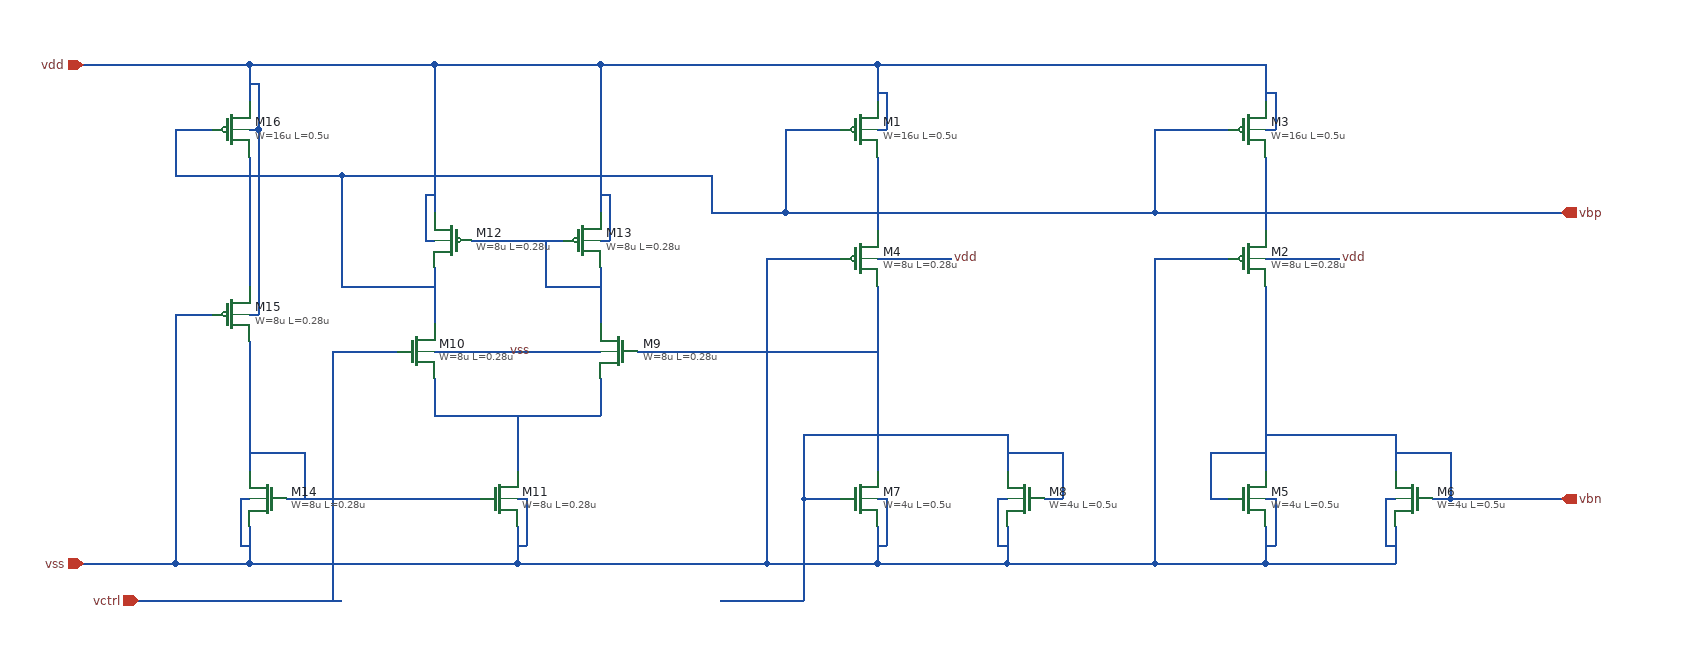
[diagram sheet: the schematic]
v {xschem version=3.4.5 file_version=1.2
}
G {}
K {}
V {}
S {}
E {}
N 1120 -460 1120 -420 {
lab=#net1}
N 1120 -500 1120 -460 {
lab=#net1}
N 1120 -600 1120 -560 {
lab=vdd}
N 1120 -530 1130 -530 {
lab=vdd}
N 1130 -570 1130 -530 {
lab=vdd}
N 1120 -570 1130 -570 {
lab=vdd}
N 1120 -390 1200 -390 {
lab=vdd}
N 1000 -390 1080 -390 {
lab=vss}
N 1120 -360 1120 -280 {
lab=vbn}
N 1120 -280 1120 -160 {
lab=vbn}
N 1120 -100 1120 -60 {
lab=vss}
N 1120 -130 1130 -130 {
lab=vss}
N 1130 -130 1130 -80 {
lab=vss}
N 1120 -80 1130 -80 {
lab=vss}
N 1260 -100 1260 -60 {
lab=vss}
N 1120 -60 1260 -60 {
lab=vss}
N 1250 -130 1260 -130 {
lab=vss}
N 1250 -130 1250 -80 {
lab=vss}
N 1250 -80 1260 -80 {
lab=vss}
N 1260 -200 1260 -160 {
lab=vbn}
N 1120 -200 1260 -200 {
lab=vbn}
N 1300 -130 1320 -130 {
lab=vbn}
N 1060 -130 1080 -130 {
lab=vbn}
N 1060 -180 1060 -130 {
lab=vbn}
N 1060 -180 1120 -180 {
lab=vbn}
N 1320 -130 1440 -130 {
lab=vbn}
N 1000 -390 1000 -60 {
lab=vss}
N 1000 -60 1120 -60 {
lab=vss}
N 1000 -530 1080 -530 {
lab=vbp}
N 1000 -530 1000 -440 {
lab=vbp}
N 920 -440 1000 -440 {
lab=vbp}
N 1000 -440 1440 -440 {
lab=vbp}
N 700 -460 700 -420 {
lab=#net2}
N 700 -500 700 -460 {
lab=#net2}
N 700 -600 700 -560 {
lab=vdd}
N 700 -530 710 -530 {
lab=vdd}
N 710 -570 710 -530 {
lab=vdd}
N 700 -570 710 -570 {
lab=vdd}
N 700 -390 780 -390 {
lab=vdd}
N 700 -360 700 -280 {
lab=vctrl}
N 700 -280 700 -160 {
lab=vctrl}
N 700 -100 700 -60 {
lab=vss}
N 700 -130 710 -130 {
lab=vss}
N 710 -130 710 -80 {
lab=vss}
N 700 -80 710 -80 {
lab=vss}
N 840 -100 840 -60 {
lab=vss}
N 700 -60 840 -60 {
lab=vss}
N 830 -130 840 -130 {
lab=vss}
N 830 -130 830 -80 {
lab=vss}
N 830 -80 840 -80 {
lab=vss}
N 840 -200 840 -160 {
lab=vctrl}
N 700 -200 840 -200 {
lab=vctrl}
N 880 -130 900 -130 {
lab=vctrl}
N 900 -180 900 -130 {
lab=vctrl}
N 840 -180 900 -180 {
lab=vctrl}
N 840 -60 1000 -60 {
lab=vss}
N 600 -530 660 -530 {
lab=vbp}
N 600 -530 600 -440 {
lab=vbp}
N 600 -440 920 -440 {
lab=vbp}
N 580 -390 660 -390 {
lab=vss}
N 580 -390 580 -60 {
lab=vss}
N 580 -60 700 -60 {
lab=vss}
N 620 -130 660 -130 {
lab=vctrl}
N 620 -130 620 -20 {
lab=vctrl}
N 530 -20 620 -20 {
lab=vctrl}
N 700 -600 1120 -600 {
lab=vdd}
N 220 -260 220 -220 {
lab=#net3}
N 220 -220 400 -220 {
lab=#net3}
N 400 -260 400 -220 {
lab=#net3}
N 120 -290 180 -290 {
lab=vctrl}
N 440 -290 500 -290 {
lab=vctrl}
N 310 -220 310 -160 {
lab=#net3}
N 310 -100 310 -60 {
lab=vss}
N 310 -60 580 -60 {
lab=vss}
N 310 -130 320 -130 {
lab=vss}
N 320 -130 320 -80 {
lab=vss}
N 310 -80 320 -80 {
lab=vss}
N 200 -130 270 -130 {
lab=#net4}
N 220 -290 400 -290 {
lab=vss}
N 220 -380 220 -320 {
lab=vbp}
N 400 -380 400 -320 {
lab=#net5}
N 220 -600 220 -440 {
lab=vdd}
N 220 -600 400 -600 {
lab=vdd}
N 400 -600 400 -440 {
lab=vdd}
N 260 -410 360 -410 {
lab=#net5}
N 340 -360 400 -360 {
lab=#net5}
N 340 -410 340 -360 {
lab=#net5}
N 400 -410 410 -410 {
lab=vdd}
N 410 -460 410 -410 {
lab=vdd}
N 400 -460 410 -460 {
lab=vdd}
N 210 -410 220 -410 {
lab=vdd}
N 210 -460 210 -410 {
lab=vdd}
N 210 -460 220 -460 {
lab=vdd}
N 20 -100 20 -60 {
lab=vss}
N 20 -60 310 -60 {
lab=vss}
N 20 -300 20 -160 {
lab=#net4}
N 60 -130 200 -130 {
lab=#net4}
N 20 -180 80 -180 {
lab=#net4}
N 80 -180 80 -130 {
lab=#net4}
N 10 -130 20 -130 {
lab=vss}
N 10 -130 10 -80 {
lab=vss}
N 10 -80 20 -80 {
lab=vss}
N -60 -330 -20 -330 {
lab=vss}
N -60 -330 -60 -60 {
lab=vss}
N -60 -60 20 -60 {
lab=vss}
N 20 -440 20 -360 {
lab=#net6}
N 20 -500 20 -440 {
lab=#net6}
N 20 -600 20 -560 {
lab=vdd}
N 20 -600 220 -600 {
lab=vdd}
N 20 -530 30 -530 {
lab=vdd}
N 30 -580 30 -530 {
lab=vdd}
N 20 -580 30 -580 {
lab=vdd}
N 20 -330 30 -330 {
lab=vdd}
N 30 -530 30 -330 {
lab=vdd}
N 120 -360 220 -360 {
lab=vbp}
N 120 -480 120 -360 {
lab=vbp}
N -60 -480 120 -480 {
lab=vbp}
N -60 -530 -60 -480 {
lab=vbp}
N -60 -530 -20 -530 {
lab=vbp}
N 120 -480 520 -480 {
lab=vbp}
N 520 -480 520 -440 {
lab=vbp}
N 520 -440 600 -440 {
lab=vbp}
N -100 -20 120 -20 {
lab=vctrl}
N 500 -290 700 -290 {
lab=vctrl}
N 400 -600 700 -600 {
lab=vdd}
N -80 -600 20 -600 {
lab=vdd}
N -100 -60 -60 -60 {
lab=vss}
N -160 -60 -100 -60 {
lab=vss}
N -160 -600 -80 -600 {
lab=vdd}
N 110 -290 110 -280 {
lab=vctrl}
N 110 -290 120 -290 {
lab=vctrl}
N 1260 -180 1320 -180 {
lab=vbn}
N 1320 -180 1320 -140 {
lab=vbn}
N 1320 -140 1320 -130 {
lab=vbn}
N 110 -280 110 -20 {
lab=vctrl}
N 620 -200 620 -130 {
lab=vctrl}
N 620 -200 700 -200 {
lab=vctrl}
C {symbols/pfet_03v3.sym} 1100 -530 0 0 {name=M3
L=0.5u
W=16u
nf=1
m=1
ad="'int((nf+1)/2) * W/nf * 0.18u'"
pd="'2*int((nf+1)/2) * (W/nf + 0.18u)'"
as="'int((nf+2)/2) * W/nf * 0.18u'"
ps="'2*int((nf+2)/2) * (W/nf + 0.18u)'"
nrd="'0.18u / W'" nrs="'0.18u / W'"
sa=0 sb=0 sd=0
model=pfet_03v3
spiceprefix=X
}
C {symbols/pfet_03v3.sym} 1100 -390 0 0 {name=M2
L=0.28u
W=8u
nf=1
m=2
ad="'int((nf+1)/2) * W/nf * 0.18u'"
pd="'2*int((nf+1)/2) * (W/nf + 0.18u)'"
as="'int((nf+2)/2) * W/nf * 0.18u'"
ps="'2*int((nf+2)/2) * (W/nf + 0.18u)'"
nrd="'0.18u / W'" nrs="'0.18u / W'"
sa=0 sb=0 sd=0
model=pfet_03v3
spiceprefix=X
}
C {symbols/nfet_03v3.sym} 1100 -130 0 0 {name=M5
L=0.5u
W=4u
nf=1
m=1
ad="'int((nf+1)/2) * W/nf * 0.18u'"
pd="'2*int((nf+1)/2) * (W/nf + 0.18u)'"
as="'int((nf+2)/2) * W/nf * 0.18u'"
ps="'2*int((nf+2)/2) * (W/nf + 0.18u)'"
nrd="'0.18u / W'" nrs="'0.18u / W'"
sa=0 sb=0 sd=0
model=nfet_03v3
spiceprefix=X
}
C {symbols/nfet_03v3.sym} 1280 -130 0 1 {name=M6
L=0.5u
W=4u
nf=1
m=1
ad="'int((nf+1)/2) * W/nf * 0.18u'"
pd="'2*int((nf+1)/2) * (W/nf + 0.18u)'"
as="'int((nf+2)/2) * W/nf * 0.18u'"
ps="'2*int((nf+2)/2) * (W/nf + 0.18u)'"
nrd="'0.18u / W'" nrs="'0.18u / W'"
sa=0 sb=0 sd=0
model=nfet_03v3
spiceprefix=X
}
C {lab_wire.sym} 1200 -390 0 1 {name=p10 sig_type=std_logic lab=vdd}
C {symbols/pfet_03v3.sym} 680 -530 0 0 {name=M1
L=0.5u
W=16u
nf=1
m=1
ad="'int((nf+1)/2) * W/nf * 0.18u'"
pd="'2*int((nf+1)/2) * (W/nf + 0.18u)'"
as="'int((nf+2)/2) * W/nf * 0.18u'"
ps="'2*int((nf+2)/2) * (W/nf + 0.18u)'"
nrd="'0.18u / W'" nrs="'0.18u / W'"
sa=0 sb=0 sd=0
model=pfet_03v3
spiceprefix=X
}
C {symbols/pfet_03v3.sym} 680 -390 0 0 {name=M4
L=0.28u
W=8u
nf=1
m=2
ad="'int((nf+1)/2) * W/nf * 0.18u'"
pd="'2*int((nf+1)/2) * (W/nf + 0.18u)'"
as="'int((nf+2)/2) * W/nf * 0.18u'"
ps="'2*int((nf+2)/2) * (W/nf + 0.18u)'"
nrd="'0.18u / W'" nrs="'0.18u / W'"
sa=0 sb=0 sd=0
model=pfet_03v3
spiceprefix=X
}
C {symbols/nfet_03v3.sym} 680 -130 0 0 {name=M7
L=0.5u
W=4u
nf=1
m=1
ad="'int((nf+1)/2) * W/nf * 0.18u'"
pd="'2*int((nf+1)/2) * (W/nf + 0.18u)'"
as="'int((nf+2)/2) * W/nf * 0.18u'"
ps="'2*int((nf+2)/2) * (W/nf + 0.18u)'"
nrd="'0.18u / W'" nrs="'0.18u / W'"
sa=0 sb=0 sd=0
model=nfet_03v3
spiceprefix=X
}
C {symbols/nfet_03v3.sym} 860 -130 0 1 {name=M8
L=0.5u
W=4u
nf=1
m=1
ad="'int((nf+1)/2) * W/nf * 0.18u'"
pd="'2*int((nf+1)/2) * (W/nf + 0.18u)'"
as="'int((nf+2)/2) * W/nf * 0.18u'"
ps="'2*int((nf+2)/2) * (W/nf + 0.18u)'"
nrd="'0.18u / W'" nrs="'0.18u / W'"
sa=0 sb=0 sd=0
model=nfet_03v3
spiceprefix=X
}
C {lab_wire.sym} 780 -390 0 1 {name=p1 sig_type=std_logic lab=vdd}
C {symbols/nfet_03v3.sym} 420 -290 0 1 {name=M9
L=0.28u
W=8u
nf=1
m=2
ad="'int((nf+1)/2) * W/nf * 0.18u'"
pd="'2*int((nf+1)/2) * (W/nf + 0.18u)'"
as="'int((nf+2)/2) * W/nf * 0.18u'"
ps="'2*int((nf+2)/2) * (W/nf + 0.18u)'"
nrd="'0.18u / W'" nrs="'0.18u / W'"
sa=0 sb=0 sd=0
model=nfet_03v3
spiceprefix=X
}
C {symbols/nfet_03v3.sym} 200 -290 0 0 {name=M10
L=0.28u
W=8u
nf=1
m=2
ad="'int((nf+1)/2) * W/nf * 0.18u'"
pd="'2*int((nf+1)/2) * (W/nf + 0.18u)'"
as="'int((nf+2)/2) * W/nf * 0.18u'"
ps="'2*int((nf+2)/2) * (W/nf + 0.18u)'"
nrd="'0.18u / W'" nrs="'0.18u / W'"
sa=0 sb=0 sd=0
model=nfet_03v3
spiceprefix=X
}
C {symbols/nfet_03v3.sym} 290 -130 0 0 {name=M11
L=0.28u
W=8u
nf=1
m=1
ad="'int((nf+1)/2) * W/nf * 0.18u'"
pd="'2*int((nf+1)/2) * (W/nf + 0.18u)'"
as="'int((nf+2)/2) * W/nf * 0.18u'"
ps="'2*int((nf+2)/2) * (W/nf + 0.18u)'"
nrd="'0.18u / W'" nrs="'0.18u / W'"
sa=0 sb=0 sd=0
model=nfet_03v3
spiceprefix=X
}
C {symbols/pfet_03v3.sym} 240 -410 0 1 {name=M12
L=0.28u
W=8u
nf=1
m=4
ad="'int((nf+1)/2) * W/nf * 0.18u'"
pd="'2*int((nf+1)/2) * (W/nf + 0.18u)'"
as="'int((nf+2)/2) * W/nf * 0.18u'"
ps="'2*int((nf+2)/2) * (W/nf + 0.18u)'"
nrd="'0.18u / W'" nrs="'0.18u / W'"
sa=0 sb=0 sd=0
model=pfet_03v3
spiceprefix=X
}
C {symbols/pfet_03v3.sym} 380 -410 0 0 {name=M13
L=0.28u
W=8u
nf=1
m=4
ad="'int((nf+1)/2) * W/nf * 0.18u'"
pd="'2*int((nf+1)/2) * (W/nf + 0.18u)'"
as="'int((nf+2)/2) * W/nf * 0.18u'"
ps="'2*int((nf+2)/2) * (W/nf + 0.18u)'"
nrd="'0.18u / W'" nrs="'0.18u / W'"
sa=0 sb=0 sd=0
model=pfet_03v3
spiceprefix=X
}
C {symbols/nfet_03v3.sym} 40 -130 0 1 {name=M14
L=0.28u
W=8u
nf=1
m=1
ad="'int((nf+1)/2) * W/nf * 0.18u'"
pd="'2*int((nf+1)/2) * (W/nf + 0.18u)'"
as="'int((nf+2)/2) * W/nf * 0.18u'"
ps="'2*int((nf+2)/2) * (W/nf + 0.18u)'"
nrd="'0.18u / W'" nrs="'0.18u / W'"
sa=0 sb=0 sd=0
model=nfet_03v3
spiceprefix=X
}
C {symbols/pfet_03v3.sym} 0 -330 0 0 {name=M15
L=0.28u
W=8u
nf=1
m=2
ad="'int((nf+1)/2) * W/nf * 0.18u'"
pd="'2*int((nf+1)/2) * (W/nf + 0.18u)'"
as="'int((nf+2)/2) * W/nf * 0.18u'"
ps="'2*int((nf+2)/2) * (W/nf + 0.18u)'"
nrd="'0.18u / W'" nrs="'0.18u / W'"
sa=0 sb=0 sd=0
model=pfet_03v3
spiceprefix=X
}
C {symbols/pfet_03v3.sym} 0 -530 0 0 {name=M16
L=0.5u
W=16u
nf=1
m=1
ad="'int((nf+1)/2) * W/nf * 0.18u'"
pd="'2*int((nf+1)/2) * (W/nf + 0.18u)'"
as="'int((nf+2)/2) * W/nf * 0.18u'"
ps="'2*int((nf+2)/2) * (W/nf + 0.18u)'"
nrd="'0.18u / W'" nrs="'0.18u / W'"
sa=0 sb=0 sd=0
model=pfet_03v3
spiceprefix=X
}
C {ipin.sym} -160 -600 0 0 {name=p2 lab=vdd}
C {ipin.sym} -100 -20 0 0 {name=p3 lab=vctrl}
C {ipin.sym} -160 -60 0 0 {name=p4 lab=vss}
C {opin.sym} 1440 -440 0 0 {name=p5 lab=vbp}
C {opin.sym} 1440 -130 0 0 {name=p6 lab=vbn}
C {lab_wire.sym} 300 -290 0 1 {name=p7 sig_type=std_logic lab=vss}
